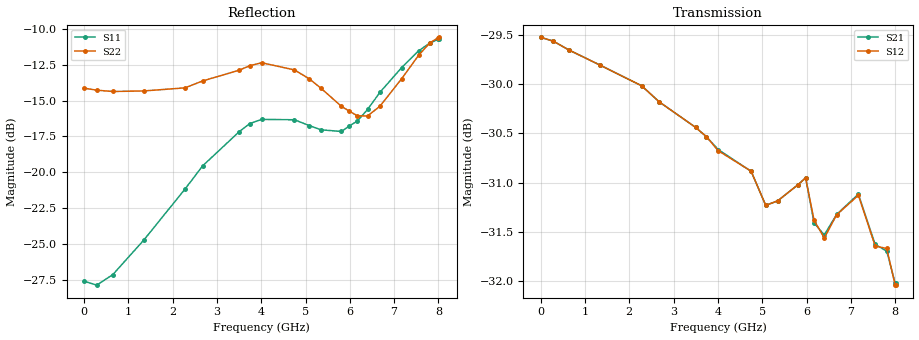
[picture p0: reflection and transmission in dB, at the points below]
! DEVICE ID: PE43712
! File Path: z:\PE43713\PE43713_CHAR_NOM_04292014\AMB\3p300\LS_ATT_28p25dB\PE43713_AMB_3p300V_3p000V_0p000V_LS_ATT_28p25dB_S2P_SN_10_A0139A.s2p
! Serial: 10
! Lot: A0139A
! Temp: 25C
! VDD: 3.300
! VSS: 0.000
! Control_Hi: 3.000
! Control_Lo: 0.000
! Attenuation Step: 28.25dB
! Port 1: RF1
! Port 2: RF2
! ThroughPath:1-2
! IDD: 0.0001454839
! ISS: -1.594e-007
#  Hz  S  RI  R  50
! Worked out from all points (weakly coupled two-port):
!   801 points, 10 MHz to 8.01 GHz, reference 50 ohm
!   highest |S21| = -29.52 dB at 10 MHz (marker M1); lowest = -32.0 dB at 8 GHz (marker M2)
!   lowest |S11| = -27.9 dB at 290 MHz (marker M3), VSWR 1.08, Z = 46.3 + j1.23 ohm
!   |S11| at or under -10 dB: start of sweep to end of sweep
!   |S22| runs from -16.1 to -10.6 dB; largest |S21 - S12| = 0.00013
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1e7  -0.0416 0.000899  0.0334 -0.000148  0.0334 -0.000131  -0.1966 0.00127
2.9e8  -0.0381 0.0133  0.0331 -0.00315  0.0331 -0.00315  -0.1923 0.0215
6.5e8  -0.0337 0.0281  0.0322 -0.00677  0.0322 -0.00676  -0.1858 0.0462
1.35e9  -0.021 0.054  0.0296 -0.013  0.0296 -0.013  -0.169 0.0917
2.28e9  0.00948 0.0868  0.0245 -0.0199  0.0245 -0.0199  -0.1285 0.1495
2.68e9  0.025 0.1023  0.0217 -0.0221  0.0217 -0.0221  -0.1066 0.1791
3.5e9  0.0483 0.1297  0.0156 -0.0257  0.0156 -0.0257  -0.0731 0.215
3.74e9  0.0533 0.1379  0.0137 -0.0264  0.0137 -0.0264  -0.0676 0.2256
4.01e9  0.0582 0.1415  0.0116 -0.0269  0.0115 -0.0269  -0.0629 0.2329
4.75e9  0.0719 0.1345  0.00612 -0.0279  0.00613 -0.0279  -0.0381 0.2245
5.08e9  0.0815 0.1207  0.00367 -0.0272  0.00368 -0.0272  -0.0261 0.2106
5.35e9  0.091 0.1073  0.00225 -0.0275  0.00228 -0.0275  -0.0147 0.1959
5.81e9  0.1135 0.0799  -0.0011 -0.0281  -0.00103 -0.0281  0.0234 0.1683
5.98e9  0.1262 0.0709  -0.00291 -0.0282  -0.00286 -0.0282  0.0414 0.1584
6.17e9  0.1385 0.0602  -0.00457 -0.0265  -0.00451 -0.0266  0.0634 0.1441
6.4e9  0.1573 0.0521  -0.00467 -0.0261  -0.00468 -0.026  0.0922 0.1274
6.68e9  0.1852 0.0435  -0.00638 -0.0264  -0.00633 -0.0264  0.1286 0.1114
7.17e9  0.2293 0.0363  -0.0111 -0.0255  -0.011 -0.0255  0.1862 0.1019
7.55e9  0.2628 0.0373  -0.0133 -0.0226  -0.0132 -0.0226  0.2339 0.104
7.81e9  0.2801 0.0407  -0.0145 -0.0216  -0.0145 -0.0217  0.262 0.1084
8e9  0.2882 0.0428  -0.0147 -0.0203  -0.0146 -0.0203  0.2748 0.1078
8.01e9  0.2886 0.0433  -0.0147 -0.0203  -0.0146 -0.0203  0.2755 0.1077
